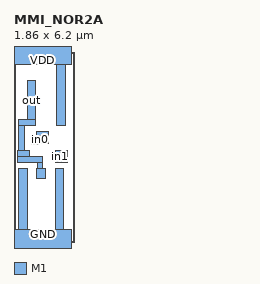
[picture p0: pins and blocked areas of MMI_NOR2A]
MACRO MMI_NOR2A
	CLASS CORE ;
	FOREIGN MMI_NOR2A 0 0 ;
	SIZE 1.86 BY 6.2 ;
	SYMMETRY X Y ;
	SITE CORE1 ;
	PIN out
		DIRECTION output ;
		USE SIGNAL ;
		PORT
			LAYER M1 ;
			RECT 0.435 3.995 0.715 5.27 ;
			LAYER M1 ;
			RECT 0.15 3.8 0.715 3.995 ;
			LAYER M1 ;
			RECT 0.15 2.98 0.345 3.8 ;
			LAYER M1 ;
			RECT 0.12 2.795 0.5 2.98 ;
			LAYER M1 ;
			RECT 0.12 2.6 0.945 2.795 ;
			LAYER M1 ;
			RECT 0.755 2.395 0.945 2.6 ;
			LAYER M1 ;
			RECT 0.75 2.08 1.03 2.395 ;
		END
		AntennaDiffArea 0.7777 ;
	END out
	PIN in1
		DIRECTION input ;
		USE SIGNAL ;
		PORT
			LAYER M1 ;
			RECT 1.36 2.93 1.74 2.98 ;
			LAYER M1 ;
			RECT 1.27 2.65 1.74 2.93 ;
			LAYER M1 ;
			RECT 1.36 2.6 1.74 2.65 ;
		END
		AntennaGateArea 0.28875 ;
	END in1
	PIN GND
		DIRECTION inout ;
		USE GROUND ;
		PORT
			LAYER M1 ;
			RECT 0.16 0.42 0.44 2.395 ;
			LAYER M1 ;
			RECT 1.34 0.42 1.62 2.395 ;
			LAYER M1 ;
			RECT 0 -0.42 1.86 0.42 ;
		END
	END GND
	PIN VDD
		DIRECTION inout ;
		USE POWER ;
		PORT
			LAYER M1 ;
			RECT 0 5.78 1.86 6.62 ;
			LAYER M1 ;
			RECT 1.395 3.8 1.675 5.78 ;
		END
	END VDD
	PIN in0
		DIRECTION input ;
		USE SIGNAL ;
		PORT
			LAYER M1 ;
			RECT 0.74 3.465 1.12 3.6 ;
			LAYER M1 ;
			RECT 0.555 3.22 1.12 3.465 ;
			LAYER M1 ;
			RECT 0.555 3.185 0.835 3.22 ;
		END
		AntennaGateArea 0.28875 ;
	END in0
	OBS
	END
END MMI_NOR2A
